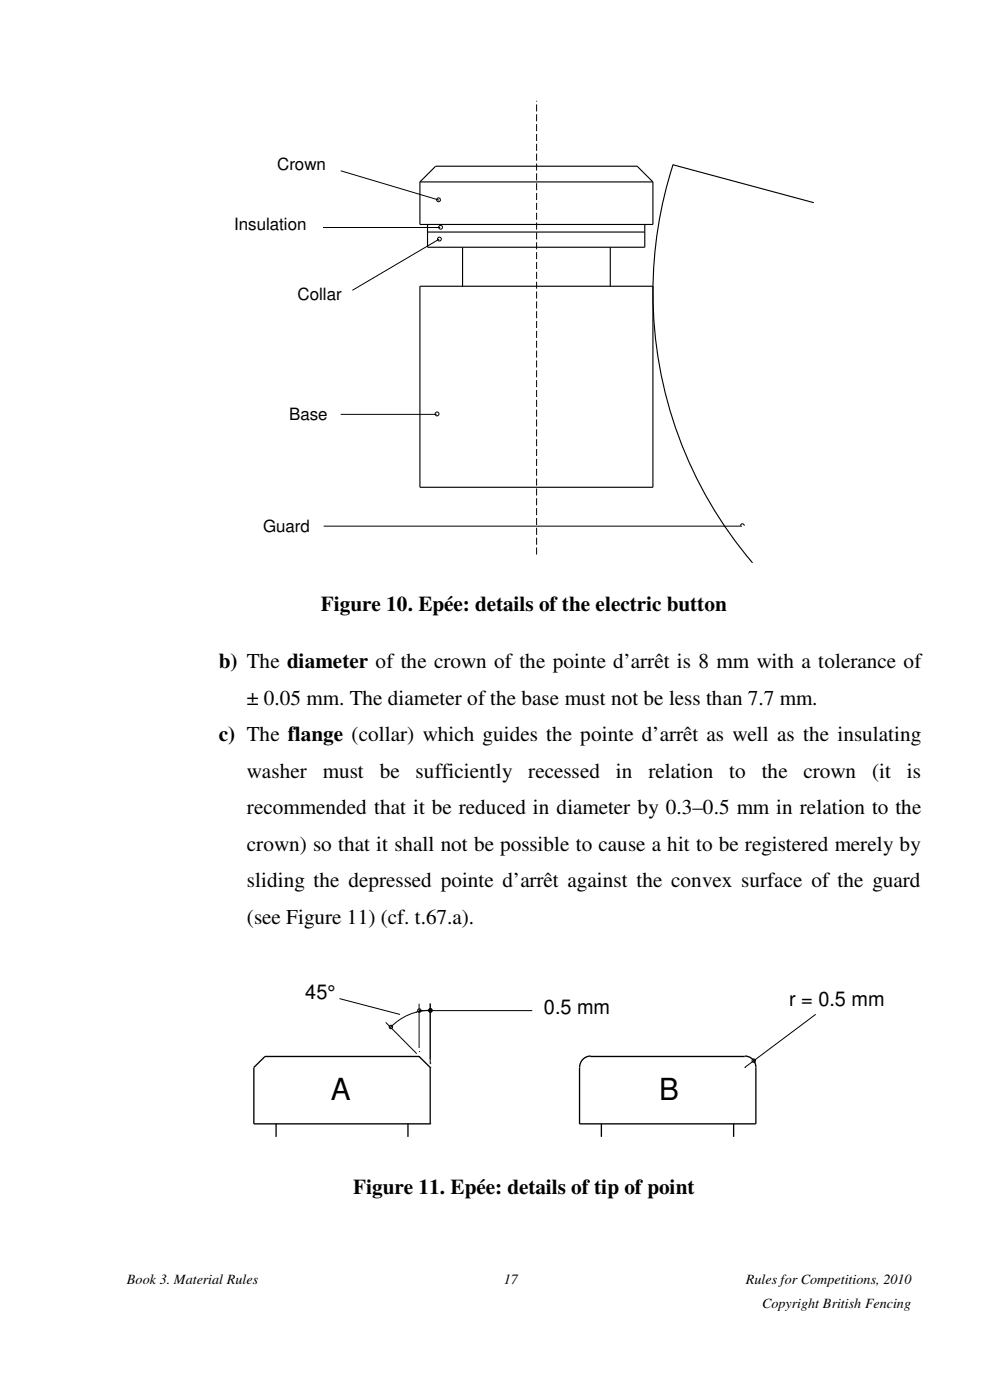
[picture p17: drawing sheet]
<svg xmlns="http://www.w3.org/2000/svg" width="148mm" height="210mm" viewBox="0 0 148 210" stroke-linecap="round" stroke-linejoin="round" font-family="sans-serif">
<defs><g id="words">
<g font-size="4.6">
<text x="49.5" y="164.9">A</text>
<text x="98.8" y="165">B</text>
</g>
<g font-size="3.2">
<text x="48.1" y="91.6">Figure 10. Epée: details of the electric button</text>
<text x="32.8" y="100.2">b) The diameter of the crown of the pointe d’arrêt is 8 mm with a tolerance of</text>
<text x="37" y="105.7">± 0.05 mm. The diameter of the base must not be less than 7.7 mm.</text>
<text x="32.8" y="111.1">c) The flange (collar) which guides the pointe d’arrêt as well as the insulating</text>
<text x="37" y="116.6">washer</text>
<text x="48.4" y="116.6">must</text>
<text x="56.9" y="116.6">be</text>
<text x="62.3" y="116.6">sufficiently</text>
<text x="79.1" y="116.6">recessed</text>
<text x="92.3" y="116.6">in</text>
<text x="97.1" y="116.6">relation</text>
<text x="109.3" y="116.6">to</text>
<text x="114.1" y="116.6">the</text>
<text x="120.4" y="116.6">crown</text>
<text x="130.7" y="116.6">(it</text>
<text x="135.9" y="116.6">is</text>
<text x="37" y="122.1">recommended that it be reduced in diameter by 0.3–0.5 mm in relation to the</text>
<text x="37" y="127.6">crown) so that it shall not be possible to cause a hit to be registered merely by</text>
<text x="37" y="133">sliding the depressed pointe d’arrêt against the convex surface of the guard</text>
<text x="37" y="138.5">(see Figure 11) (cf. t.67.a).</text>
<text x="52.9" y="178.9">Figure 11. Epée: details of tip of point</text>
</g>
<g font-size="3">
<text x="45.7" y="149.7">45°</text>
<text x="81.5" y="152">0.5 mm</text>
<text x="118.2" y="150.9">r = 0.5 mm</text>
</g>
<g font-size="2.5">
<text x="41.5" y="25.5">Crown</text>
<text x="35.1" y="34.5">Insulation</text>
<text x="44.6" y="45">Collar</text>
<text x="43.3" y="63">Base</text>
<text x="39.4" y="79.7">Guard</text>
</g>
<g font-size="2.1">
<text x="19" y="192.6">Book 3. Material Rules</text>
<text x="75.5" y="192.6">17</text>
<text x="111.7" y="192.6">Rules for Competitions, 2010</text>
<text x="114.2" y="196.1">Copyright British Fencing</text>
</g>
</g></defs>
<path d="M80.4 83.1v-68" fill="none" stroke="#000" stroke-width=".15" stroke-dasharray="1.1 .4" stroke-linecap="butt"/>
<g fill="none" stroke="#000" stroke-width=".15">
<path d="M48.4 34.1h17.6M51 25.6l14.8 4.4M65.8 35.9l-13 7.6M48.5 78.9h62.7M51 62.1h14.4M110.9 78.8a.29 .29 0 0 1 .3-.3 .29 .29 0 0 1 .3 .3M50.9 149.7l9 2.4M57.8 153.3l4.6 4.7M62.3 151.8h.1M62.8 157.7h.1M62.8 158.4h.1M62.8 150.5v6.6"/>
<path d="M62.8 151.5h16.9M64.5 159.4h.1M64.5 151.5h.1M64.5 150.4v9.2M64.5 151.5a8.3 8.3 0 0 0-5.9 2.5M112.9 159.1h.1M112.9 159.1l-1.3 .9M122.2 152.1l-9.3 7M64.5 160h.1M64.5 168.5h.1M111.6 160h.1"/>
<circle cx="65.7" cy="30" r=".29"/>
<circle cx="65.8" cy="35.8" r=".29"/>
<circle cx="66" cy="34.1" r=".29"/>
<circle cx="65.5" cy="62.1" r=".29"/>
<circle cx="58.6" cy="154" r=".26"/>
<circle cx="62.8" cy="151.5" r=".26"/>
<circle cx="64.5" cy="151.5" r=".26"/>
<circle cx="112.9" cy="159" r=".26"/>
</g>
<path d="M62.9 27.3v6.4h34.9v-6.4M62.9 27.3h34.9M62.9 27.3l2.4-2.4h30.2l2.3 2.4M64.1 33.7v3.4h32.5v-3.4M64.1 34.8h32.5M69.3 37.1v5.8M91.4 37.1v5.8M100.8 24.7l21.1 5.7M100.8 24.7a62.5 62.5 0 0 0 11.9 59.7M62.9 42.9h34.9v30.2h-34.9z" fill="none" stroke="#000" stroke-width=".17"/>
<path d="M88.4 158.4h23.2M88.5 158.3a1.67 1.67 0 0 0-1.7 1.7M111.6 158.3a1.67 1.67 0 0 1 1.6 1.7v8.5h-26.4v-8.5M38 160l1.7-1.6h23.1l1.7 1.6v8.5h-26.5zM41.4 168.5v1.9M61.1 168.5v1.9M90.1 168.5v1.9M109.9 168.5v1.9" fill="none" stroke="#000" stroke-width=".2"/>
<use href="#words"/>
</svg>
